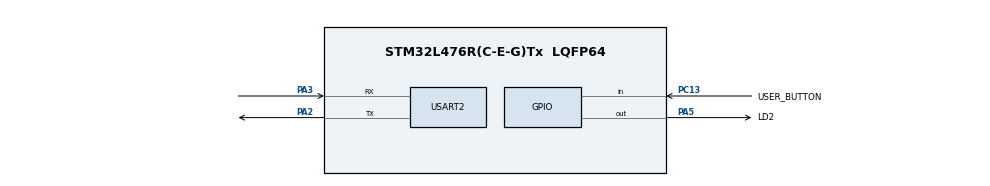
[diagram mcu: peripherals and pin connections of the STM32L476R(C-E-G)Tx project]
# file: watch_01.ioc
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Mcu.Family=STM32L4
Mcu.Name=STM32L476R(C-E-G)Tx
Mcu.Package=LQFP64
NVIC.PriorityGroup=NVIC_PRIORITYGROUP_4
PA13\ (JTMS-SWDIO).Mode=Serial_Wire
PA13\ (JTMS-SWDIO).Signal=SYS_JTMS-SWDIO
PA14\ (JTCK-SWCLK).Mode=Serial_Wire
PA14\ (JTCK-SWCLK).Signal=SYS_JTCK-SWCLK
PA2.Mode=Asynchronous
PA2.Signal=USART2_TX
PA3.Mode=Asynchronous
PA3.Signal=USART2_RX
PA5.GPIO_Label=LD2
PA5.Signal=GPIO_Output
PC13.GPIO_Label=USER_BUTTON
PC13.Signal=GPIO_Input
PC14-OSC32_IN\ (PC14).Mode=LSE-External-Oscillator
PC14-OSC32_IN\ (PC14).Signal=RCC_OSC32_IN
PC15-OSC32_OUT\ (PC15).Mode=LSE-External-Oscillator
PC15-OSC32_OUT\ (PC15).Signal=RCC_OSC32_OUT
ProjectManager.HeapSize=0x200
ProjectManager.StackSize=0x400
ProjectManager.TargetToolchain=STM32CubeIDE
RCC.ADCFreq_Value=16000000
RCC.AHBFreq_Value=4000000
RCC.APB1Freq_Value=4000000
RCC.APB1TimFreq_Value=4000000
RCC.APB2Freq_Value=4000000
RCC.APB2TimFreq_Value=4000000
RCC.CortexFreq_Value=4000000
RCC.HCLKFreq_Value=4000000
RCC.HSE_VALUE=8000000
RCC.HSI_VALUE=16000000
RCC.MSI_VALUE=4000000
RCC.RTCClockSelection=RCC_RTCCLKSOURCE_LSE
RCC.SYSCLKFreq_VALUE=4000000
RCC.USBFreq_Value=16000000
RCC.VCOOutputFreq_Value=32000000
USART2.OverrunDisableParam=ADVFEATURE_OVERRUN_DISABLE
USART2.VirtualMode-Asynchronous=VM_ASYNC
VP_RTC_VS_RTC_Activate.Mode=RTC_Enabled
board=custom

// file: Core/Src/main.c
/* USER CODE BEGIN Header */
/**
  ******************************************************************************
  * @file           : main.c
  * @brief          : Main program body
  ******************************************************************************
  * @attention
  *
  * <h2><center>&copy; Copyright (c) 2022 STMicroelectronics.
  * All rights reserved.</center></h2>
  *
  * This software component is licensed by ST under BSD 3-Clause license,
  * the "License"; You may not use this file except in compliance with the
  * License. You may obtain a copy of the License at:
  *                        opensource.org/licenses/BSD-3-Clause
  *
  ******************************************************************************
  */
/* USER CODE END Header */
#include "main.h"
#include "rtc.h"
#include "usart.h"
#include "gpio.h"

/* USER CODE BEGIN Includes */
#include <stdio.h>
#include <string.h>
#include <stdbool.h>
/* USER CODE END Includes */

void SystemClock_Config(void);
/* USER CODE BEGIN PFP */
int __io_putchar(int ch);

bool is_button_pressed(void);
/* USER CODE END PFP */

int main(void)
{

  /* MCU Configuration--------------------------------------------------------*/

  /* Reset of all peripherals, Initializes the Flash interface and the Systick. */
  HAL_Init();

  /* Configure the system clock */
  SystemClock_Config();

  /* Initialize all configured peripherals */
  MX_GPIO_Init();
  MX_USART2_UART_Init();
  MX_RTC_Init();

  /* Infinite loop */
  /* USER CODE BEGIN WHILE */
    while (1)
    {
        RTC_TimeTypeDef time;
        RTC_DateTypeDef date;

        if (is_button_pressed())
        {
            RTC_TimeTypeDef init_time = {0};
            RTC_DateTypeDef init_date = {0};
            while (is_button_pressed())
            {
            }

            //leap year test
            init_time.Hours = 23;
            init_time.Minutes = 59;
            init_time.Seconds = 50;
            init_date.Year = 20;
            init_date.Month = 2;
            init_date.Date = 28;
            init_date.WeekDay = RTC_WEEKDAY_WEDNESDAY;

            HAL_RTC_SetTime(&hrtc, &init_time, RTC_FORMAT_BIN);
            HAL_RTC_SetDate(&hrtc, &init_date, RTC_FORMAT_BIN);
        }

        HAL_RTC_GetTime(&hrtc, &time, RTC_FORMAT_BIN);
        HAL_RTC_GetDate(&hrtc, &date, RTC_FORMAT_BIN);

        printf("RTC: %04d.%02d.%02d\n", 2000+date.Year, date.Month, date.Date);
        printf("Dzien tygodnia: %d\n", date.WeekDay);
        printf("Aktualny czas: %02d:%02d:%02d\n", time.Hours, time.Minutes, time.Seconds);
        HAL_Delay(200);
    /* USER CODE END WHILE */

    }
}

void SystemClock_Config(void)
{
  RCC_OscInitTypeDef RCC_OscInitStruct = {0};
  RCC_ClkInitTypeDef RCC_ClkInitStruct = {0};
  RCC_PeriphCLKInitTypeDef PeriphClkInit = {0};

  /** Configure LSE Drive Capability
  */
  HAL_PWR_EnableBkUpAccess();
  __HAL_RCC_LSEDRIVE_CONFIG(RCC_LSEDRIVE_LOW);
  /** Initializes the RCC Oscillators according to the specified parameters
  * in the RCC_OscInitTypeDef structure.
  */
  RCC_OscInitStruct.OscillatorType = RCC_OSCILLATORTYPE_LSE|RCC_OSCILLATORTYPE_MSI;
  RCC_OscInitStruct.LSEState = RCC_LSE_ON;
  RCC_OscInitStruct.MSIState = RCC_MSI_ON;
  RCC_OscInitStruct.MSICalibrationValue = 0;
  RCC_OscInitStruct.MSIClockRange = RCC_MSIRANGE_6;
  RCC_OscInitStruct.PLL.PLLState = RCC_PLL_ON;
  RCC_OscInitStruct.PLL.PLLSource = RCC_PLLSOURCE_MSI;
  RCC_OscInitStruct.PLL.PLLM = 1;
  RCC_OscInitStruct.PLL.PLLN = 40;
  RCC_OscInitStruct.PLL.PLLP = RCC_PLLP_DIV7;
  RCC_OscInitStruct.PLL.PLLQ = RCC_PLLQ_DIV2;
  RCC_OscInitStruct.PLL.PLLR = RCC_PLLR_DIV2;
  if (HAL_RCC_OscConfig(&RCC_OscInitStruct) != HAL_OK)
  {
    Error_Handler();
  }
  /** Initializes the CPU, AHB and APB buses clocks
  */
  RCC_ClkInitStruct.ClockType = RCC_CLOCKTYPE_HCLK|RCC_CLOCKTYPE_SYSCLK
                              |RCC_CLOCKTYPE_PCLK1|RCC_CLOCKTYPE_PCLK2;
  RCC_ClkInitStruct.SYSCLKSource = RCC_SYSCLKSOURCE_PLLCLK;
  RCC_ClkInitStruct.AHBCLKDivider = RCC_SYSCLK_DIV1;
  RCC_ClkInitStruct.APB1CLKDivider = RCC_HCLK_DIV1;
  RCC_ClkInitStruct.APB2CLKDivider = RCC_HCLK_DIV1;

  if (HAL_RCC_ClockConfig(&RCC_ClkInitStruct, FLASH_LATENCY_4) != HAL_OK)
  {
    Error_Handler();
  }
  PeriphClkInit.PeriphClockSelection = RCC_PERIPHCLK_RTC|RCC_PERIPHCLK_USART2;
  PeriphClkInit.Usart2ClockSelection = RCC_USART2CLKSOURCE_PCLK1;
  PeriphClkInit.RTCClockSelection = RCC_RTCCLKSOURCE_LSE;
  if (HAL_RCCEx_PeriphCLKConfig(&PeriphClkInit) != HAL_OK)
  {
    Error_Handler();
  }
  /** Configure the main internal regulator output voltage
  */
  if (HAL_PWREx_ControlVoltageScaling(PWR_REGULATOR_VOLTAGE_SCALE1) != HAL_OK)
  {
    Error_Handler();
  }
  /** Enable MSI Auto calibration
  */
  HAL_RCCEx_EnableMSIPLLMode();
}

/* USER CODE BEGIN 4 */
int __io_putchar(int ch)
{
    if (ch == '\n')
    {
        uint8_t ch2 = '\r';
        HAL_UART_Transmit(&huart2, &ch2, 1, HAL_MAX_DELAY);
    }

    HAL_UART_Transmit(&huart2, (uint8_t *) &ch, 1, HAL_MAX_DELAY);
    return 1;
}

bool is_button_pressed(void)
{
    if (HAL_GPIO_ReadPin(USER_BUTTON_GPIO_Port, USER_BUTTON_Pin) == GPIO_PIN_RESET)
    {
        return true;
    }
    else
    {
        return false;
    }
}
/* USER CODE END 4 */

void Error_Handler(void)
{
    __disable_irq();
    while (1)
    {
    }
}

/************************ (C) COPYRIGHT STMicroelectronics *****END OF FILE****/
